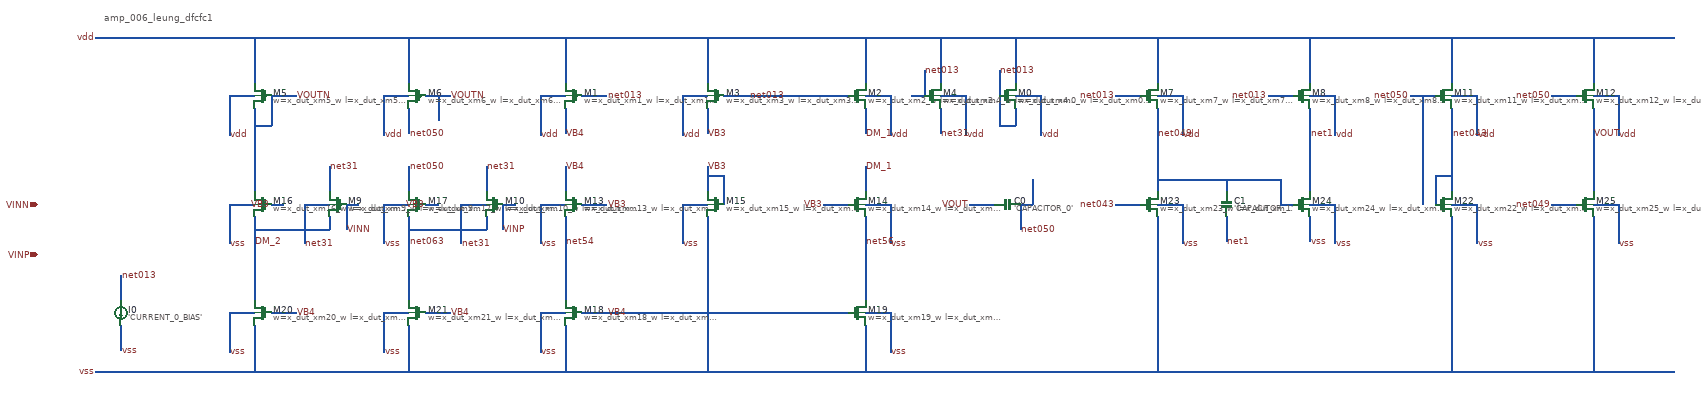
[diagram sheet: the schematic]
v {xschem version=3.4.6 file_version=1.2}
G {}
K {}
V {}
S {}
E {}
T {amp_006_leung_dfcfc1} -1910 -200 0 0 0.4 0.4 {}
C {devices/capa_np.sym} 255 260 1 0 {name=C0 value='CAPACITOR_0'}
C {devices/capa_np.sym} 780 260 0 0 {name=C1 value='CAPACITOR_1'}
C {devices/isource_np.sym} -1870 520 0 0 {name=I0 value='CURRENT_0_BIAS'}
C {devices/sg13_lv_pmos_np.sym} 255 0 0 0 {name=M0 model=sg13_lv_pmos spiceprefix=X w=x_dut_xm0_w l=x_dut_xm0_l m=x_dut_xm0_m}
C {devices/sg13_lv_pmos_np.sym} -785 0 0 1 {name=M1 model=sg13_lv_pmos spiceprefix=X w=x_dut_xm1_w l=x_dut_xm1_l m=x_dut_xm1_m}
C {devices/sg13_lv_pmos_np.sym} -975 260 0 1 {name=M10 model=sg13_lv_pmos spiceprefix=X w=x_dut_xm10_w l=x_dut_xm10_l m=x_dut_xm10_m}
C {devices/sg13_lv_pmos_np.sym} 1300 0 0 0 {name=M11 model=sg13_lv_pmos spiceprefix=X w=x_dut_xm11_w l=x_dut_xm11_l m=x_dut_xm11_m}
C {devices/sg13_lv_pmos_np.sym} 1640 0 0 0 {name=M12 model=sg13_lv_pmos spiceprefix=X w=x_dut_xm12_w l=x_dut_xm12_l m=x_dut_xm12_m}
C {devices/sg13_lv_nmos_np.sym} -785 260 0 1 {name=M13 model=sg13_lv_nmos spiceprefix=X w=x_dut_xm13_w l=x_dut_xm13_l m=x_dut_xm13_m}
C {devices/sg13_lv_nmos_np.sym} -105 260 0 0 {name=M14 model=sg13_lv_nmos spiceprefix=X w=x_dut_xm14_w l=x_dut_xm14_l m=x_dut_xm14_m}
C {devices/sg13_lv_nmos_np.sym} -445 260 0 1 {name=M15 model=sg13_lv_nmos spiceprefix=X w=x_dut_xm15_w l=x_dut_xm15_l m=x_dut_xm15_m}
C {devices/sg13_lv_nmos_np.sym} -1530 260 0 1 {name=M16 model=sg13_lv_nmos spiceprefix=X w=x_dut_xm16_w l=x_dut_xm16_l m=x_dut_xm16_m}
C {devices/sg13_lv_nmos_np.sym} -1160 260 0 1 {name=M17 model=sg13_lv_nmos spiceprefix=X w=x_dut_xm17_w l=x_dut_xm17_l m=x_dut_xm17_m}
C {devices/sg13_lv_nmos_np.sym} -785 520 0 1 {name=M18 model=sg13_lv_nmos spiceprefix=X w=x_dut_xm18_w l=x_dut_xm18_l m=x_dut_xm18_m}
C {devices/sg13_lv_nmos_np.sym} -105 520 0 0 {name=M19 model=sg13_lv_nmos spiceprefix=X w=x_dut_xm19_w l=x_dut_xm19_l m=x_dut_xm19_m}
C {devices/sg13_lv_pmos_np.sym} -105 0 0 0 {name=M2 model=sg13_lv_pmos spiceprefix=X w=x_dut_xm2_w l=x_dut_xm2_l m=x_dut_xm2_m}
C {devices/sg13_lv_nmos_np.sym} -1530 520 0 1 {name=M20 model=sg13_lv_nmos spiceprefix=X w=x_dut_xm20_w l=x_dut_xm20_l m=x_dut_xm20_m}
C {devices/sg13_lv_nmos_np.sym} -1160 520 0 1 {name=M21 model=sg13_lv_nmos spiceprefix=X w=x_dut_xm21_w l=x_dut_xm21_l m=x_dut_xm21_m}
C {devices/sg13_lv_nmos_np.sym} 1300 260 0 0 {name=M22 model=sg13_lv_nmos spiceprefix=X w=x_dut_xm22_w l=x_dut_xm22_l m=x_dut_xm22_m}
C {devices/sg13_lv_nmos_np.sym} 595 260 0 0 {name=M23 model=sg13_lv_nmos spiceprefix=X w=x_dut_xm23_w l=x_dut_xm23_l m=x_dut_xm23_m}
C {devices/sg13_lv_nmos_np.sym} 960 260 0 0 {name=M24 model=sg13_lv_nmos spiceprefix=X w=x_dut_xm24_w l=x_dut_xm24_l m=x_dut_xm24_m}
C {devices/sg13_lv_nmos_np.sym} 1640 260 0 0 {name=M25 model=sg13_lv_nmos spiceprefix=X w=x_dut_xm25_w l=x_dut_xm25_l m=x_dut_xm25_m}
C {devices/sg13_lv_pmos_np.sym} -445 0 0 1 {name=M3 model=sg13_lv_pmos spiceprefix=X w=x_dut_xm3_w l=x_dut_xm3_l m=x_dut_xm3_m}
C {devices/sg13_lv_pmos_np.sym} 75 0 0 0 {name=M4 model=sg13_lv_pmos spiceprefix=X w=x_dut_xm4_w l=x_dut_xm4_l m=x_dut_xm4_m}
C {devices/sg13_lv_pmos_np.sym} -1530 0 0 1 {name=M5 model=sg13_lv_pmos spiceprefix=X w=x_dut_xm5_w l=x_dut_xm5_l m=x_dut_xm5_m}
C {devices/sg13_lv_pmos_np.sym} -1160 0 0 1 {name=M6 model=sg13_lv_pmos spiceprefix=X w=x_dut_xm6_w l=x_dut_xm6_l m=x_dut_xm6_m}
C {devices/sg13_lv_pmos_np.sym} 595 0 0 0 {name=M7 model=sg13_lv_pmos spiceprefix=X w=x_dut_xm7_w l=x_dut_xm7_l m=x_dut_xm7_m}
C {devices/sg13_lv_pmos_np.sym} 960 0 0 0 {name=M8 model=sg13_lv_pmos spiceprefix=X w=x_dut_xm8_w l=x_dut_xm8_l m=x_dut_xm8_m}
C {devices/sg13_lv_pmos_np.sym} -1350 260 0 1 {name=M9 model=sg13_lv_pmos spiceprefix=X w=x_dut_xm9_w l=x_dut_xm9_l m=x_dut_xm9_m}
N -1870 430 -1870 490 {}
N -1870 550 -1870 610 {}
N -1610 0 -1610 94 {}
N -1610 260 -1610 354 {}
N -1610 520 -1610 614 {}
N -1550 -140 -1550 -30 {}
N -1550 30 -1550 230 {}
N -1550 290 -1550 490 {}
N -1550 550 -1550 660 {}
N -1510 0 -1510 70 {}
N -1430 260 -1430 354 {}
N -1370 170 -1370 230 {}
N -1370 290 -1370 320 {}
N -1330 260 -1330 320 {}
N -1240 0 -1240 94 {}
N -1240 260 -1240 354 {}
N -1240 520 -1240 614 {}
N -1180 -140 -1180 -30 {}
N -1180 30 -1180 90 {}
N -1180 170 -1180 230 {}
N -1180 290 -1180 490 {}
N -1180 550 -1180 660 {}
N -1110 0 -1110 60 {}
N -1055 260 -1055 354 {}
N -995 170 -995 230 {}
N -995 290 -995 320 {}
N -955 260 -955 320 {}
N -865 0 -865 94 {}
N -865 260 -865 354 {}
N -865 520 -865 614 {}
N -805 -140 -805 -30 {}
N -805 30 -805 90 {}
N -805 170 -805 230 {}
N -805 290 -805 490 {}
N -805 550 -805 660 {}
N -525 0 -525 94 {}
N -525 260 -525 354 {}
N -465 -140 -465 -30 {}
N -465 30 -465 90 {}
N -465 170 -465 230 {}
N -465 290 -465 660 {}
N -425 190 -425 260 {}
N -85 -140 -85 -30 {}
N -85 30 -85 90 {}
N -85 170 -85 230 {}
N -85 290 -85 490 {}
N -85 550 -85 660 {}
N -25 0 -25 94 {}
N -25 260 -25 354 {}
N -25 520 -25 614 {}
N 55 -60 55 0 {}
N 95 -140 95 -30 {}
N 95 30 95 90 {}
N 155 0 155 94 {}
N 235 -60 235 70 {}
N 275 -140 275 -30 {}
N 275 30 275 70 {}
N 285 260 285 320 {}
N 315 200 315 260 {}
N 335 0 335 94 {}
N 615 -140 615 -30 {}
N 615 30 615 230 {}
N 615 290 615 660 {}
N 675 0 675 94 {}
N 675 260 675 354 {}
N 780 200 780 230 {}
N 780 290 780 350 {}
N 910 200 910 260 {}
N 980 -140 980 -30 {}
N 980 30 980 230 {}
N 980 290 980 350 {}
N 1040 0 1040 94 {}
N 1040 260 1040 354 {}
N 1250 0 1250 260 {}
N 1280 190 1280 260 {}
N 1320 -140 1320 -30 {}
N 1320 30 1320 230 {}
N 1320 290 1320 660 {}
N 1380 0 1380 94 {}
N 1380 260 1380 354 {}
N 1660 -140 1660 -30 {}
N 1660 30 1660 230 {}
N 1660 290 1660 660 {}
N 1720 0 1720 94 {}
N 1720 260 1720 354 {}
N -1930 -140 1855 -140 {}
N -1610 0 -1550 0 {}
N -1510 0 -1450 0 {}
N -1240 0 -1180 0 {}
N -1140 0 -1080 0 {}
N -865 0 -805 0 {}
N -765 0 -705 0 {}
N -525 0 -465 0 {}
N -425 0 -125 0 {}
N -85 0 -25 0 {}
N 25 0 55 0 {}
N 95 0 155 0 {}
N 275 0 335 0 {}
N 515 0 575 0 {}
N 615 0 675 0 {}
N 880 0 940 0 {}
N 980 0 1040 0 {}
N 1220 0 1280 0 {}
N 1320 0 1380 0 {}
N 1560 0 1620 0 {}
N 1660 0 1720 0 {}
N -1550 70 -1510 70 {}
N 235 70 275 70 {}
N -465 190 -425 190 {}
N 1280 190 1320 190 {}
N 615 200 910 200 {}
N -1610 260 -1550 260 {}
N -1510 260 -1480 260 {}
N -1430 260 -1370 260 {}
N -1330 260 -1300 260 {}
N -1240 260 -1180 260 {}
N -1140 260 -1110 260 {}
N -1055 260 -995 260 {}
N -955 260 -925 260 {}
N -865 260 -805 260 {}
N -765 260 -705 260 {}
N -525 260 -465 260 {}
N -185 260 -125 260 {}
N -85 260 -25 260 {}
N 165 260 225 260 {}
N 285 260 315 260 {}
N 515 260 575 260 {}
N 615 260 675 260 {}
N 910 260 940 260 {}
N 980 260 1040 260 {}
N 1320 260 1380 260 {}
N 1560 260 1620 260 {}
N 1660 260 1720 260 {}
N -1550 320 -1370 320 {}
N -1180 320 -995 320 {}
N -1610 520 -1550 520 {}
N -1510 520 -1450 520 {}
N -1240 520 -1180 520 {}
N -1140 520 -1080 520 {}
N -865 520 -805 520 {}
N -765 520 -125 520 {}
N -85 520 -25 520 {}
N -1930 660 1855 660 {}
C {devices/lab_wire.sym} -1930 -140 0 0 {name=l0 lab=vdd}
C {devices/lab_wire.sym} -1930 660 0 0 {name=l1 lab=vss}
C {devices/lab_wire.sym} -85 90 2 0 {name=l2 lab=DM_1}
C {devices/lab_wire.sym} -85 170 0 1 {name=l3 lab=DM_1}
C {devices/lab_wire.sym} -1550 350 2 0 {name=l4 lab=DM_2}
C {devices/lab_wire.sym} -1510 260 0 0 {name=l5 lab=VB3}
C {devices/lab_wire.sym} -1140 260 0 0 {name=l6 lab=VB3}
C {devices/lab_wire.sym} -705 260 0 1 {name=l7 lab=VB3}
C {devices/lab_wire.sym} -465 90 2 0 {name=l8 lab=VB3}
C {devices/lab_wire.sym} -465 170 0 1 {name=l9 lab=VB3}
C {devices/lab_wire.sym} -185 260 0 0 {name=l10 lab=VB3}
C {devices/lab_wire.sym} -1450 520 0 1 {name=l11 lab=VB4}
C {devices/lab_wire.sym} -1080 520 0 1 {name=l12 lab=VB4}
C {devices/lab_wire.sym} -805 90 2 0 {name=l13 lab=VB4}
C {devices/lab_wire.sym} -805 170 0 1 {name=l14 lab=VB4}
C {devices/lab_wire.sym} -705 520 0 1 {name=l15 lab=VB4}
C {devices/lab_wire.sym} -1330 320 2 0 {name=l16 lab=VINN}
C {devices/lab_wire.sym} -955 320 2 0 {name=l17 lab=VINP}
C {devices/lab_wire.sym} 165 260 0 0 {name=l18 lab=VOUT}
C {devices/lab_wire.sym} 1660 90 2 0 {name=l19 lab=VOUT}
C {devices/lab_wire.sym} -1450 0 0 1 {name=l20 lab=VOUTN}
C {devices/lab_wire.sym} -1080 0 0 1 {name=l21 lab=VOUTN}
C {devices/lab_wire.sym} -705 0 0 1 {name=l22 lab=net013}
C {devices/lab_wire.sym} -365 0 0 1 {name=l23 lab=net013}
C {devices/lab_wire.sym} 55 -60 0 1 {name=l24 lab=net013}
C {devices/lab_wire.sym} 235 -60 0 1 {name=l25 lab=net013}
C {devices/lab_wire.sym} 515 0 0 0 {name=l26 lab=net013}
C {devices/lab_wire.sym} 880 0 0 0 {name=l27 lab=net013}
C {devices/lab_wire.sym} 515 260 0 0 {name=l28 lab=net043}
C {devices/lab_wire.sym} 1320 90 2 0 {name=l29 lab=net043}
C {devices/lab_wire.sym} 615 90 2 0 {name=l30 lab=net049}
C {devices/lab_wire.sym} 1560 260 0 0 {name=l31 lab=net049}
C {devices/lab_wire.sym} -1180 90 2 0 {name=l32 lab=net050}
C {devices/lab_wire.sym} -1180 170 0 1 {name=l33 lab=net050}
C {devices/lab_wire.sym} 285 320 2 0 {name=l34 lab=net050}
C {devices/lab_wire.sym} 1220 0 0 0 {name=l35 lab=net050}
C {devices/lab_wire.sym} 1560 0 0 0 {name=l36 lab=net050}
C {devices/lab_wire.sym} -1180 350 2 0 {name=l37 lab=net063}
C {devices/lab_wire.sym} 780 350 2 0 {name=l38 lab=net1}
C {devices/lab_wire.sym} 980 90 2 0 {name=l39 lab=net1}
C {devices/lab_wire.sym} -1370 170 0 1 {name=l40 lab=net31}
C {devices/lab_wire.sym} -995 170 0 1 {name=l41 lab=net31}
C {devices/lab_wire.sym} 95 90 2 0 {name=l42 lab=net31}
C {devices/lab_wire.sym} -805 350 2 0 {name=l43 lab=net54}
C {devices/lab_wire.sym} -85 350 2 0 {name=l44 lab=net56}
C {devices/lab_wire.sym} -1055 354 2 0 {name=l45 lab=net31}
C {devices/lab_wire.sym} -1430 354 2 0 {name=l46 lab=net31}
C {devices/lab_wire.sym} 335 94 2 0 {name=l47 lab=vdd}
C {devices/lab_wire.sym} -865 94 2 0 {name=l48 lab=vdd}
C {devices/lab_wire.sym} 1380 94 2 0 {name=l49 lab=vdd}
C {devices/lab_wire.sym} 1720 94 2 0 {name=l50 lab=vdd}
C {devices/lab_wire.sym} -25 94 2 0 {name=l51 lab=vdd}
C {devices/lab_wire.sym} -525 94 2 0 {name=l52 lab=vdd}
C {devices/lab_wire.sym} 155 94 2 0 {name=l53 lab=vdd}
C {devices/lab_wire.sym} -1610 94 2 0 {name=l54 lab=vdd}
C {devices/lab_wire.sym} -1240 94 2 0 {name=l55 lab=vdd}
C {devices/lab_wire.sym} 675 94 2 0 {name=l56 lab=vdd}
C {devices/lab_wire.sym} 1040 94 2 0 {name=l57 lab=vdd}
C {devices/lab_wire.sym} -865 354 2 0 {name=l58 lab=vss}
C {devices/lab_wire.sym} -25 354 2 0 {name=l59 lab=vss}
C {devices/lab_wire.sym} -525 354 2 0 {name=l60 lab=vss}
C {devices/lab_wire.sym} -1610 354 2 0 {name=l61 lab=vss}
C {devices/lab_wire.sym} -1240 354 2 0 {name=l62 lab=vss}
C {devices/lab_wire.sym} -865 614 2 0 {name=l63 lab=vss}
C {devices/lab_wire.sym} -25 614 2 0 {name=l64 lab=vss}
C {devices/lab_wire.sym} -1610 614 2 0 {name=l65 lab=vss}
C {devices/lab_wire.sym} -1240 614 2 0 {name=l66 lab=vss}
C {devices/lab_wire.sym} 1380 354 2 0 {name=l67 lab=vss}
C {devices/lab_wire.sym} 675 354 2 0 {name=l68 lab=vss}
C {devices/lab_wire.sym} 1040 354 2 0 {name=l69 lab=vss}
C {devices/lab_wire.sym} 1720 354 2 0 {name=l70 lab=vss}
C {devices/lab_wire.sym} -1870 430 0 1 {name=l71 lab=net013}
C {devices/lab_wire.sym} -1870 610 2 0 {name=l72 lab=vss}
C {devices/lab_wire.sym} 980 350 2 0 {name=l73 lab=vss}
C {devices/ipin.sym} -2070 260 0 0 {name=p0 lab=VINN}
C {devices/ipin.sym} -2070 380 0 0 {name=p1 lab=VINP}
